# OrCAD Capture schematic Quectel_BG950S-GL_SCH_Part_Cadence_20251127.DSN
size A2

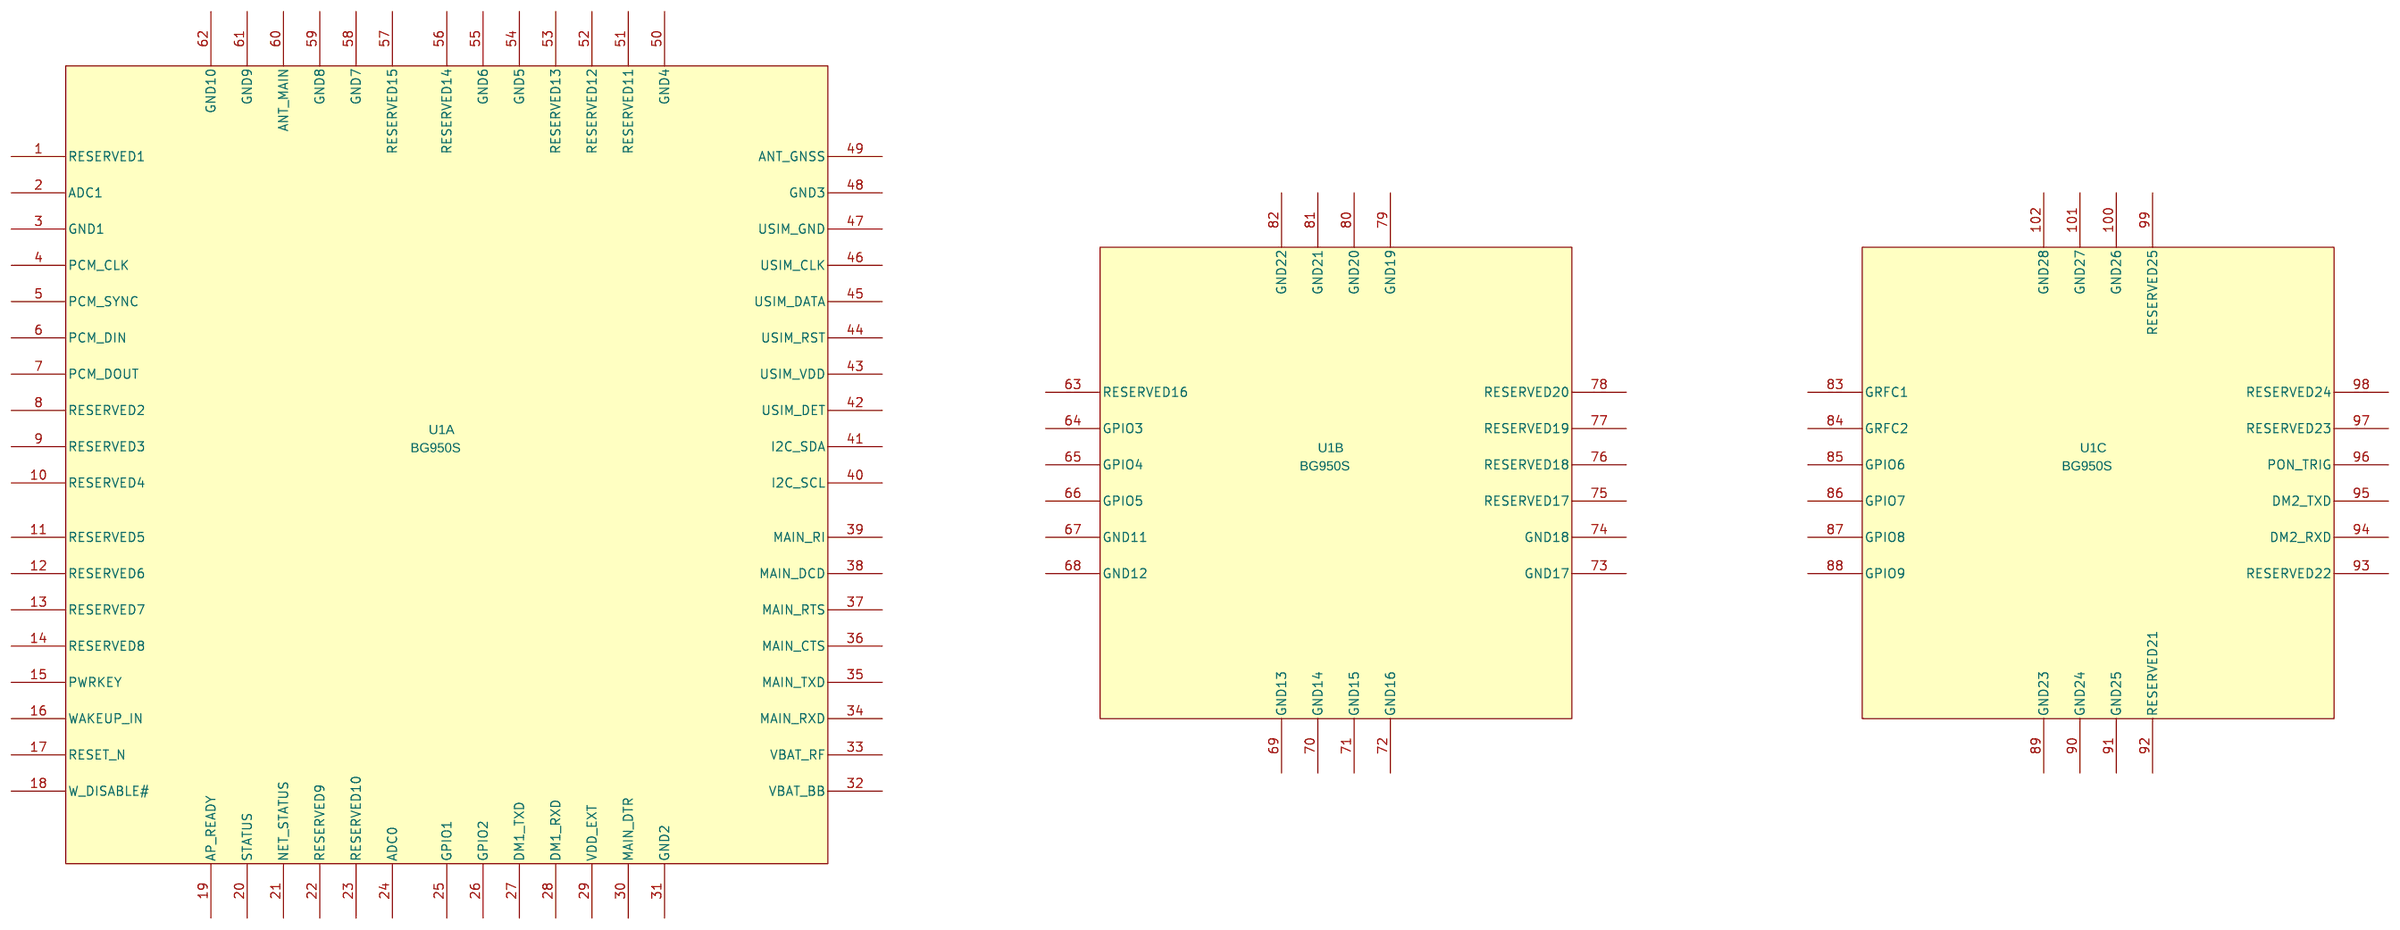
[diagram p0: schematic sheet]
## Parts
U1  BG950S  [BG950S]  (sections A,B,C)

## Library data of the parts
U1 = BG950S

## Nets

Not connected (* = marked no-connect by the designer): U1 1(RESERVED1) 2(ADC1) 3(GND1) 4(PCM_CLK) 5(PCM_SYNC) 6(PCM_DIN) 7(PCM_DOUT) 8(RESERVED2) 9(RESERVED3) 10(RESERVED4) 11(RESERVED5) 12(RESERVED6) 13(RESERVED7) 14(RESERVED8) 15(PWRKEY) 16(WAKEUP_IN) 17(RESET_N) 18(W_DISABLE#) 19(AP_READY) 20(STATUS) 21(NET_STATUS) 22(RESERVED9) 23(RESERVED10) 24(ADC0) 25(GPIO1) 26(GPIO2) 27(DM1_TXD) 28(DM1_RXD) 29(VDD_EXT) 30(MAIN_DTR) 31(GND2) 32(VBAT_BB) 33(VBAT_RF) 34(MAIN_RXD) 35(MAIN_TXD) 36(MAIN_CTS) 37(MAIN_RTS) 38(MAIN_DCD) 39(MAIN_RI) 40(I2C_SCL) 41(I2C_SDA) 42(USIM_DET) 43(USIM_VDD) 44(USIM_RST) 45(USIM_DATA) 46(USIM_CLK) 47(USIM_GND) 48(GND3) 49(ANT_GNSS) 50(GND4) 51(RESERVED11) 52(RESERVED12) 53(RESERVED13) 54(GND5) 55(GND6) 56(RESERVED14) 57(RESERVED15) 58(GND7) 59(GND8) 60(ANT_MAIN) 61(GND9) 62(GND10) 63(RESERVED16) 64(GPIO3) 65(GPIO4) 66(GPIO5) 67(GND11) 68(GND12) 69(GND13) 70(GND14) 71(GND15) 72(GND16) 73(GND17) 74(GND18) 75(RESERVED17) 76(RESERVED18) 77(RESERVED19) 78(RESERVED20) 79(GND19) 80(GND20) 81(GND21) 82(GND22) 83(GRFC1) 84(GRFC2) 85(GPIO6) 86(GPIO7) 87(GPIO8) 88(GPIO9) 89(GND23) 90(GND24) 91(GND25) 92(RESERVED21) 93(RESERVED22) 94(DM2_RXD) 95(DM2_TXD) 96(PON_TRIG) 97(RESERVED23) 98(RESERVED24) 99(RESERVED25) 100(GND26) 101(GND27) 102(GND28)
